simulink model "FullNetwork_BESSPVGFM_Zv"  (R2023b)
settings: Solver=ode15s  StartTime=0.0  StopTime=140  RelTol=1e-3
PreLoadFcn:
  | Ts=50e-6;
model workspace (MAT data in the model file):
  Cf1 = 0.02
  Cf2 = 0.02
  Kffi1 = 0.9
  Kffi2 = 0.9
  Kffi3 = 0.9
  Kffv1 = 1
  Kffv2 = 1
  Kffv3 = 1
  Ki_cc1 = 5.9
  Ki_cc2 = 5.9
  Ki_cc3 = 5.9
  Ki_q1 = 0.0001
  Ki_q2 = 0.0001
  Ki_q3 = 0.0001
  Ki_vc1 = 150
  Ki_vc2 = 150
  Ki_vc3 = 150
  Kp_cc1 = 0.015
  Kp_cc2 = 0.015
  Kp_vc1 = 15
  Kp_vc2 = 15
  Kp_vc3 = 5
  Lf1 = 4.75e-06
  Lf2 = 4.75e-06
  Rf1 = 0.0005
  Rf2 = 0.0005
  Rf3 = 0.0005
  Rv1 = 0.0003
  Rv2 = 0.0003
  Snom1 = 100000000
  Snom2 = 100000000
  Vdc1 = 2000
  Vdc2 = 2000
  Vdc3 = 2000
  Xv1 = 0.0009
  Xv2 = 0.0009
  fnom1 = 50
  fnom2 = 50
  mp1 = 6.25e-08
  mp2 = 6.25e-08
  nq1 = 4.69166666667e-07
  nq2 = 4.69166666667e-07
  tau1 = 0.001
  tau2 = 0.001
  tau3 = 0.001
  vnom1 = 690
  vnom2 = 690
  vnom3 = 690
undefined symbols (not defined in the file or in its folder): Armidale, DiscIntNeverNeededParam, find_system, Gunnedah, Innerell, Ion, Lithium, Morree, Narrabri, Tamworth
libraries: spsThreePhaseBreakerLib x41, simulink_extras x16, spsThreePhaseVIMeasurementLib x14, spsThreePhaseSeriesRLCLoadLib x14, spsabctodq0Lib x12, spsThreePhaseTransformerTwoWindingsLib x11, slpidlib x8, powerlib_extras x8, spsLoadFlowBusLib x8, spsThreePhasePISectionLineLib x8, spsFirstOrderFilterLib x6, simulink x6
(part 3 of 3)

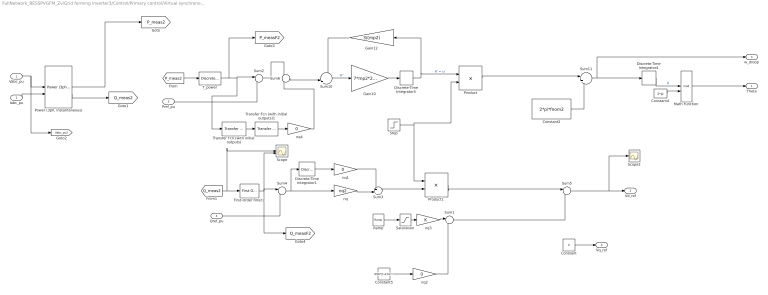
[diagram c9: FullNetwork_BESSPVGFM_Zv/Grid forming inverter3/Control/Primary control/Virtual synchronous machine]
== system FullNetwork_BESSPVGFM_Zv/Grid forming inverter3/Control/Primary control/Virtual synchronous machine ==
  Vabc_pu : Inport
  Iabc_pu : Inport  Port=2
  Pref_pu : Inport  Port=3
  Qref_pu : Inport  Port=4
  Constant : Constant  Value=0
  Constant2 : Constant  Value=2*pi*fnom2
  Constant4 : Constant  Value=2*pi
  Constant5 : Constant  Value=690*(1.414/1.732)
  Discrete-Time Integrator1 : DiscreteIntegrator  gainval=Ki_q  SampleTime=Ts  LimitOutput=on  ICPrevOutput=DiscIntNeverNeededParam  ICPrevScaledInput=DiscIntNeverNeededParam
  Discrete-Time Integrator4 : DiscreteIntegrator  SampleTime=-1  ICPrevOutput=DiscIntNeverNeededParam  ICPrevScaledInput=DiscIntNeverNeededParam
  Discrete-Time Integrator5 : DiscreteIntegrator  SampleTime=-1  ICPrevOutput=DiscIntNeverNeededParam  ICPrevScaledInput=DiscIntNeverNeededParam
  First-Order Filter1 : spsFirstOrderFilterLib/First-Order Filter  FilterType=Lowpass  Tc=tau2  Ts=Ts  Initialize=off  Vac_Init=[0, 0, 60]  Vdc_Init=0  PlotResponse=off  FreqRange="[0,  200,  1]"
  Gain10 : Gain  Gain=7*mp2*2*pi*fnom
  Gain12 : Gain  Gain=3/(mp2)
  Math Function : Math  Operator=mod  SignedPower=on
  "Power (3ph, Instantaneous)" : spsPower3phInstantaneousLib/Power (3ph, Instantaneous)
  Product : Product
  Product1 : Product
  Ramp : simulink/Sources/Ramp  slope=100  start=1  InitialOutput=0
  Saturation : Saturate  UpperLimit=563.5  LowerLimit=0  LinearizeAsGain=off  ZeroCross=off
  Scope : Scope  NumInputPorts=2
  Scope2 : Scope
  Step : Step  Time=0  SampleTime=0
  Sum1 : Sum  Inputs=|++  InputSameDT=on  SaturateOnIntegerOverflow=on
  Sum10 : Sum  Inputs=-|+||
  Sum11 : Sum  Inputs=|++
  Sum2 : Sum  Inputs=|-+  InputSameDT=on  SaturateOnIntegerOverflow=on
  Sum3 : Sum  Inputs=++|  InputSameDT=on  SaturateOnIntegerOverflow=on
  Sum4 : Sum  Inputs=|-+  InputSameDT=on  SaturateOnIntegerOverflow=on
  Sum5 : Sum  Inputs=|++  InputSameDT=on  SaturateOnIntegerOverflow=on
  Sum6 : Sum  Inputs=+-  InputSameDT=on  SaturateOnIntegerOverflow=on
  T_power : powerlib_extras/Discrete  Control Blocks/Discrete 1st-Order Filter  FilterType=Lowpass  Tc=tau2  Ts=Ts  Initialize=on  Vac_Init=[0 0 0]  Vdc_Init=1  PlotResponse=off  param1=[1 500 0.1]
  Transfer Fcn (with initial outputs) : simulink_extras/Additional Linear/Transfer Fcn (with initial outputs)  N=[0.15 1]  D="[0.03  1]"  Y0=0  U0=0
  Transfer Fcn (with initial outputs)1 : simulink_extras/Additional Linear/Transfer Fcn (with initial outputs)  N=[0.2 0 ]  D=[0.2 1]  Y0=0  U0=0
  nq : Gain  Gain=nq2
  nq1 : Gain  Gain=0
  nq2 : Gain  Gain=0
  nq3 : Gain
  nq4 : Gain  Gain=0
  Theta : Outport
  Vd_ref : Outport  Port=2
  Vq_ref : Outport  Port=3
  w_droop : Outport  Port=4
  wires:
  Constant4/1 -> Math Function/2
  Pref_pu/1 -> Sum2/2
  Vabc_pu/1 -> [Vabc_pu2], "Power (3ph, Instantaneous)"/1
  Iabc_pu/1 -> "Power (3ph, Instantaneous)"/2
  "Power (3ph, Instantaneous)"/1 -> [P_meas2]
  "Power (3ph, Instantaneous)"/2 -> [Q_meas2]
  [P_meas2] -> T_power/1
  Math Function/1 -> Theta/1
  Discrete-Time Integrator5/1 -> Product/1, Gain12/1  "θ' = ω"
  Discrete-Time Integrator4/1 -> Math Function/1  "θ"
  Sum10/1 -> Gain10/1  "θ''"
  Gain10/1 -> Discrete-Time Integrator5/1
  Gain12/1 -> Sum10/1
  Sum11/1 -> Discrete-Time Integrator4/1, w_droop/1
  Constant2/1 -> Sum11/2
  nq/1 -> Sum3/2
  Sum4/1 -> nq/1, Discrete-Time Integrator1/1
  First-Order Filter1/1 -> [Q_measF2], Scope/2, Sum4/1
  [Q_meas2] -> Scope/1, First-Order Filter1/1
  Qref_pu/1 -> Sum4/2
  Constant/1 -> Vq_ref/1
  Discrete-Time Integrator1/1 -> nq1/1
  nq1/1 -> Sum3/1
  Sum3/1 -> Product1/2
  Product1/1 -> Sum5/1
  Ramp/1 -> Saturation/1
  Product/1 -> Sum11/1
  Step/1 -> Product/2, Product1/1
  Sum1/1 -> Sum5/2
  Constant5/1 -> nq2/1
  nq2/1 -> Sum1/2
  Saturation/1 -> nq3/1
  nq3/1 -> Sum1/1
  Sum5/1 -> Scope2/1, Vd_ref/1
  Transfer Fcn (with initial outputs)/1 -> Transfer Fcn (with initial outputs)1/1
  Transfer Fcn (with initial outputs)1/1 -> nq4/1
  T_power/1 -> [P_measF2], Transfer Fcn (with initial outputs)/1, Sum2/1
  Sum2/1 -> Sum6/1
  Sum6/1 -> Sum10/2
  nq4/1 -> Sum6/2

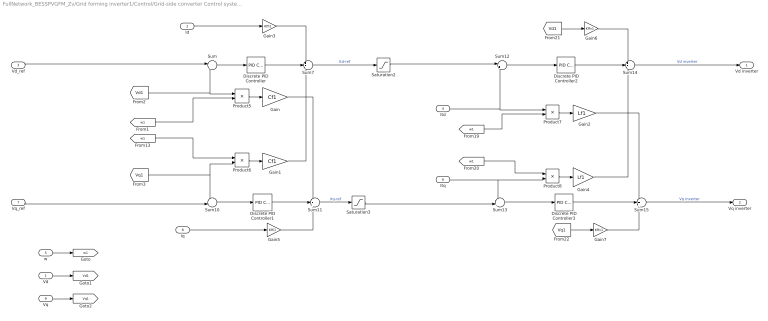
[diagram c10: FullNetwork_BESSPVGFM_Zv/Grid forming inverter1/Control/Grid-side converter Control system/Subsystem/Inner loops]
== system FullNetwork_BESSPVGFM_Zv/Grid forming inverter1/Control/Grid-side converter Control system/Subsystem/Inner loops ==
  Vd : Inport
  Id : Inport  Port=2
  Vd_ref : Inport  Port=3
  Itd : Inport  Port=4
  w : Inport  Port=5
  Itq : Inport  Port=6
  Vq_ref : Inport  Port=7
  Iq : Inport  Port=8
  Vq : Inport  Port=9
  Discrete PID Controller : slpidlib/PID Controller  Controller=PI  Form=Parallel  TimeDomain=Discrete-time  UseExternalTs=off  SampleTime=Ts  IntegratorMethod=Forward Euler  FilterMethod=Forward Euler  ControllerParametersSource=internal  P=Kp_vc1  I=Ki_vc1  UseKiTs=off  D=0  N=100  UseFilter=on  TunerSelectOption=Transfer Function Based (PID Tuner App)  InitialConditionSource=internal  InitialConditionForIntegrator=0  InitialConditionForFilter=0  DifferentiatorICPrevScaledInput=0  ExternalReset=none  TrackingMode=off  Kt=1  LimitOutput=off  SatLimitsSource=internal  UpperSaturationLimit=inf  LowerSaturationLimit=-inf  LinearizeAsGain=off  AntiWindupMode=none  Kb=1  LimitIntegrator=off  UpperIntegratorSaturationLimit=inf  LowerIntegratorSaturationLimit=-inf  POutMin=[]  POutMax=[]  IOutMin=[]  IOutMax=[]  DOutMin=[]  DOutMax=[]  NOutMin=[]  NOutMax=[]  SumOutMin=[]  SumOutMax=[]  SaturationOutMin=[]  SaturationOutMax=[]  PParamMin=[]  PParamMax=[]  IParamMin=[]  IParamMax=[]  DParamMin=[]  DParamMax=[]  NParamMin=[]  NParamMax=[]  KbParamMin=[]  KbParamMax=[]  KtParamMin=[]  KtParamMax=[]  KbOutMin=[]  KbOutMax=[]  KtOutMin=[]  KtOutMax=[]  IntegratorOutMin=[]  IntegratorOutMax=[]  FilterOutMin=[]  FilterOutMax=[]  SumI1OutMin=[]  SumI1OutMax=[]  SumI2OutMin=[]  SumI2OutMax=[]  SumI3OutMin=[]  SumI3OutMax=[]  SumI4OutMin=[]  SumI4OutMax=[]  SumDOutMin=[]  SumDOutMax=[]  DifferentiatorOutMin=[]  DifferentiatorOutMax=[]  FilterDiffOutCoefMin=[]  FilterDiffOutCoefMax=[]  ReciprocalOutMin=[]  ReciprocalOutMax=[]  SumDenOutMin=[]  SumDenOutMax=[]  SumNumOutMin=[]  SumNumOutMax=[]  DivideOutMin=[]  DivideOutMax=[]  UdiffTsProdOutMin=[]  UdiffTsProdOutMax=[]  NTsProdOutMin=[]  NTsProdOutMax=[]  UintegralTsProdOutMin=[]  UintegralTsProdOutMax=[]  UngainTsProdOutMin=[]  UngainTsProdOutMax=[]  ClampingZeroOutDataTypeStr=Inherit: Inherit via back propagation  ClampingZeroOutMin=[]  ClampingZeroOutMax=[]  FilterDenConstantOutDataTypeStr=Inherit: Inherit via back propagation  FilterDenConstantOutMin=[]  FilterDenConstantOutMax=[]  PCopyOutDataTypeStr=Inherit: Inherit via back propagation  PCopyOutMin=[]  PCopyOutMax=[]  NCopyOutDataTypeStr=Inherit: Inherit via back propagation  NCopyOutMin=[]  NCopyOutMax=[]  IntegratorContinuousStateAttributes=''  IntegratorStateMustResolveToSignalObject=off  IntegratorRTWStateStorageClass=Auto  FilterContinuousStateAttributes=''  FilterStateMustResolveToSignalObject=off  FilterRTWStateStorageClass=Auto  ParallelPVariant=InternalParameters  IdealPVariant=Disabled  IVariant=InternalParameters  DVariant=Disabled  IntegratorVariant=Discrete  SatVariant=Disabled  AWVariant=Passthrough  PCopyVariant=Disabled  TRVariant=Disabled  FdbkBlocksVariant=Forward  IdealPFdbkVariant=Disabled  SatFdbkVariant=Disabled  DerivativeFilterVariant=Disabled  NVariant=Disabled  NCopyVariant=Disabled_SignalSpec  FilterICVariant=Disabled  IntegratorICVariant=InternalICs  ExternalResetVariant=Disabled  TRSumVariant=Passthrough  SumFdbkVariant=Disabled  SumVariant=Sum_PI  TsampFilterVariant=InternalTs  TsampNgainVariant=Passthrough  TsampIntegralVariant=Disabled_SignalSpec  ExternalSaturationOutDataTypeStr=Inherit: Same as second input
  Discrete PID Controller1 : slpidlib/PID Controller  Controller=PI  Form=Parallel  TimeDomain=Discrete-time  UseExternalTs=off  SampleTime=Ts  IntegratorMethod=Forward Euler  FilterMethod=Forward Euler  ControllerParametersSource=internal  P=Kp_vc1  I=Ki_vc1  UseKiTs=off  D=0  N=100  UseFilter=on  TunerSelectOption=Transfer Function Based (PID Tuner App)  InitialConditionSource=internal  InitialConditionForIntegrator=0  InitialConditionForFilter=0  DifferentiatorICPrevScaledInput=0  ExternalReset=none  TrackingMode=off  Kt=1  LimitOutput=off  SatLimitsSource=internal  UpperSaturationLimit=inf  LowerSaturationLimit=-inf  LinearizeAsGain=off  AntiWindupMode=none  Kb=1  LimitIntegrator=off  UpperIntegratorSaturationLimit=inf  LowerIntegratorSaturationLimit=-inf  POutMin=[]  POutMax=[]  IOutMin=[]  IOutMax=[]  DOutMin=[]  DOutMax=[]  NOutMin=[]  NOutMax=[]  SumOutMin=[]  SumOutMax=[]  SaturationOutMin=[]  SaturationOutMax=[]  PParamMin=[]  PParamMax=[]  IParamMin=[]  IParamMax=[]  DParamMin=[]  DParamMax=[]  NParamMin=[]  NParamMax=[]  KbParamMin=[]  KbParamMax=[]  KtParamMin=[]  KtParamMax=[]  KbOutMin=[]  KbOutMax=[]  KtOutMin=[]  KtOutMax=[]  IntegratorOutMin=[]  IntegratorOutMax=[]  FilterOutMin=[]  FilterOutMax=[]  SumI1OutMin=[]  SumI1OutMax=[]  SumI2OutMin=[]  SumI2OutMax=[]  SumI3OutMin=[]  SumI3OutMax=[]  SumI4OutMin=[]  SumI4OutMax=[]  SumDOutMin=[]  SumDOutMax=[]  DifferentiatorOutMin=[]  DifferentiatorOutMax=[]  FilterDiffOutCoefMin=[]  FilterDiffOutCoefMax=[]  ReciprocalOutMin=[]  ReciprocalOutMax=[]  SumDenOutMin=[]  SumDenOutMax=[]  SumNumOutMin=[]  SumNumOutMax=[]  DivideOutMin=[]  DivideOutMax=[]  UdiffTsProdOutMin=[]  UdiffTsProdOutMax=[]  NTsProdOutMin=[]  NTsProdOutMax=[]  UintegralTsProdOutMin=[]  UintegralTsProdOutMax=[]  UngainTsProdOutMin=[]  UngainTsProdOutMax=[]  ClampingZeroOutDataTypeStr=Inherit: Inherit via back propagation  ClampingZeroOutMin=[]  ClampingZeroOutMax=[]  FilterDenConstantOutDataTypeStr=Inherit: Inherit via back propagation  FilterDenConstantOutMin=[]  FilterDenConstantOutMax=[]  PCopyOutDataTypeStr=Inherit: Inherit via back propagation  PCopyOutMin=[]  PCopyOutMax=[]  NCopyOutDataTypeStr=Inherit: Inherit via back propagation  NCopyOutMin=[]  NCopyOutMax=[]  IntegratorContinuousStateAttributes=''  IntegratorStateMustResolveToSignalObject=off  IntegratorRTWStateStorageClass=Auto  FilterContinuousStateAttributes=''  FilterStateMustResolveToSignalObject=off  FilterRTWStateStorageClass=Auto  ParallelPVariant=InternalParameters  IdealPVariant=Disabled  IVariant=InternalParameters  DVariant=Disabled  IntegratorVariant=Discrete  SatVariant=Disabled  AWVariant=Passthrough  PCopyVariant=Disabled  TRVariant=Disabled  FdbkBlocksVariant=Forward  IdealPFdbkVariant=Disabled  SatFdbkVariant=Disabled  DerivativeFilterVariant=Disabled  NVariant=Disabled  NCopyVariant=Disabled_SignalSpec  FilterICVariant=Disabled  IntegratorICVariant=InternalICs  ExternalResetVariant=Disabled  TRSumVariant=Passthrough  SumFdbkVariant=Disabled  SumVariant=Sum_PI  TsampFilterVariant=InternalTs  TsampNgainVariant=Passthrough  TsampIntegralVariant=Disabled_SignalSpec  ExternalSaturationOutDataTypeStr=Inherit: Same as second input
  Discrete PID Controller2 : slpidlib/PID Controller  Controller=PI  Form=Parallel  TimeDomain=Discrete-time  UseExternalTs=off  SampleTime=Ts  IntegratorMethod=Forward Euler  FilterMethod=Forward Euler  ControllerParametersSource=internal  P=Kp_cc1  I=Ki_cc1  UseKiTs=off  D=0  N=100  UseFilter=on  TunerSelectOption=Transfer Function Based (PID Tuner App)  InitialConditionSource=internal  InitialConditionForIntegrator=0  InitialConditionForFilter=0  DifferentiatorICPrevScaledInput=0  ExternalReset=none  TrackingMode=off  Kt=1  LimitOutput=off  SatLimitsSource=internal  UpperSaturationLimit=inf  LowerSaturationLimit=-inf  LinearizeAsGain=off  AntiWindupMode=none  Kb=1  LimitIntegrator=off  UpperIntegratorSaturationLimit=inf  LowerIntegratorSaturationLimit=-inf  POutMin=[]  POutMax=[]  IOutMin=[]  IOutMax=[]  DOutMin=[]  DOutMax=[]  NOutMin=[]  NOutMax=[]  SumOutMin=[]  SumOutMax=[]  SaturationOutMin=[]  SaturationOutMax=[]  PParamMin=[]  PParamMax=[]  IParamMin=[]  IParamMax=[]  DParamMin=[]  DParamMax=[]  NParamMin=[]  NParamMax=[]  KbParamMin=[]  KbParamMax=[]  KtParamMin=[]  KtParamMax=[]  KbOutMin=[]  KbOutMax=[]  KtOutMin=[]  KtOutMax=[]  IntegratorOutMin=[]  IntegratorOutMax=[]  FilterOutMin=[]  FilterOutMax=[]  SumI1OutMin=[]  SumI1OutMax=[]  SumI2OutMin=[]  SumI2OutMax=[]  SumI3OutMin=[]  SumI3OutMax=[]  SumI4OutMin=[]  SumI4OutMax=[]  SumDOutMin=[]  SumDOutMax=[]  DifferentiatorOutMin=[]  DifferentiatorOutMax=[]  FilterDiffOutCoefMin=[]  FilterDiffOutCoefMax=[]  ReciprocalOutMin=[]  ReciprocalOutMax=[]  SumDenOutMin=[]  SumDenOutMax=[]  SumNumOutMin=[]  SumNumOutMax=[]  DivideOutMin=[]  DivideOutMax=[]  UdiffTsProdOutMin=[]  UdiffTsProdOutMax=[]  NTsProdOutMin=[]  NTsProdOutMax=[]  UintegralTsProdOutMin=[]  UintegralTsProdOutMax=[]  UngainTsProdOutMin=[]  UngainTsProdOutMax=[]  ClampingZeroOutDataTypeStr=Inherit: Inherit via back propagation  ClampingZeroOutMin=[]  ClampingZeroOutMax=[]  FilterDenConstantOutDataTypeStr=Inherit: Inherit via back propagation  FilterDenConstantOutMin=[]  FilterDenConstantOutMax=[]  PCopyOutDataTypeStr=Inherit: Inherit via back propagation  PCopyOutMin=[]  PCopyOutMax=[]  NCopyOutDataTypeStr=Inherit: Inherit via back propagation  NCopyOutMin=[]  NCopyOutMax=[]  IntegratorContinuousStateAttributes=''  IntegratorStateMustResolveToSignalObject=off  IntegratorRTWStateStorageClass=Auto  FilterContinuousStateAttributes=''  FilterStateMustResolveToSignalObject=off  FilterRTWStateStorageClass=Auto  ParallelPVariant=InternalParameters  IdealPVariant=Disabled  IVariant=InternalParameters  DVariant=Disabled  IntegratorVariant=Discrete  SatVariant=Disabled  AWVariant=Passthrough  PCopyVariant=Disabled  TRVariant=Disabled  FdbkBlocksVariant=Forward  IdealPFdbkVariant=Disabled  SatFdbkVariant=Disabled  DerivativeFilterVariant=Disabled  NVariant=Disabled  NCopyVariant=Disabled_SignalSpec  FilterICVariant=Disabled  IntegratorICVariant=InternalICs  ExternalResetVariant=Disabled  TRSumVariant=Passthrough  SumFdbkVariant=Disabled  SumVariant=Sum_PI  TsampFilterVariant=InternalTs  TsampNgainVariant=Passthrough  TsampIntegralVariant=Disabled_SignalSpec  ExternalSaturationOutDataTypeStr=Inherit: Same as second input
  Discrete PID Controller3 : slpidlib/PID Controller  Controller=PI  Form=Parallel  TimeDomain=Discrete-time  UseExternalTs=off  SampleTime=Ts  IntegratorMethod=Forward Euler  FilterMethod=Forward Euler  ControllerParametersSource=internal  P=Kp_cc1  I=Ki_cc1  UseKiTs=off  D=0  N=100  UseFilter=on  TunerSelectOption=Transfer Function Based (PID Tuner App)  InitialConditionSource=internal  InitialConditionForIntegrator=0  InitialConditionForFilter=0  DifferentiatorICPrevScaledInput=0  ExternalReset=none  TrackingMode=off  Kt=1  LimitOutput=off  SatLimitsSource=internal  UpperSaturationLimit=inf  LowerSaturationLimit=-inf  LinearizeAsGain=off  AntiWindupMode=none  Kb=1  LimitIntegrator=off  UpperIntegratorSaturationLimit=inf  LowerIntegratorSaturationLimit=-inf  POutMin=[]  POutMax=[]  IOutMin=[]  IOutMax=[]  DOutMin=[]  DOutMax=[]  NOutMin=[]  NOutMax=[]  SumOutMin=[]  SumOutMax=[]  SaturationOutMin=[]  SaturationOutMax=[]  PParamMin=[]  PParamMax=[]  IParamMin=[]  IParamMax=[]  DParamMin=[]  DParamMax=[]  NParamMin=[]  NParamMax=[]  KbParamMin=[]  KbParamMax=[]  KtParamMin=[]  KtParamMax=[]  KbOutMin=[]  KbOutMax=[]  KtOutMin=[]  KtOutMax=[]  IntegratorOutMin=[]  IntegratorOutMax=[]  FilterOutMin=[]  FilterOutMax=[]  SumI1OutMin=[]  SumI1OutMax=[]  SumI2OutMin=[]  SumI2OutMax=[]  SumI3OutMin=[]  SumI3OutMax=[]  SumI4OutMin=[]  SumI4OutMax=[]  SumDOutMin=[]  SumDOutMax=[]  DifferentiatorOutMin=[]  DifferentiatorOutMax=[]  FilterDiffOutCoefMin=[]  FilterDiffOutCoefMax=[]  ReciprocalOutMin=[]  ReciprocalOutMax=[]  SumDenOutMin=[]  SumDenOutMax=[]  SumNumOutMin=[]  SumNumOutMax=[]  DivideOutMin=[]  DivideOutMax=[]  UdiffTsProdOutMin=[]  UdiffTsProdOutMax=[]  NTsProdOutMin=[]  NTsProdOutMax=[]  UintegralTsProdOutMin=[]  UintegralTsProdOutMax=[]  UngainTsProdOutMin=[]  UngainTsProdOutMax=[]  ClampingZeroOutDataTypeStr=Inherit: Inherit via back propagation  ClampingZeroOutMin=[]  ClampingZeroOutMax=[]  FilterDenConstantOutDataTypeStr=Inherit: Inherit via back propagation  FilterDenConstantOutMin=[]  FilterDenConstantOutMax=[]  PCopyOutDataTypeStr=Inherit: Inherit via back propagation  PCopyOutMin=[]  PCopyOutMax=[]  NCopyOutDataTypeStr=Inherit: Inherit via back propagation  NCopyOutMin=[]  NCopyOutMax=[]  IntegratorContinuousStateAttributes=''  IntegratorStateMustResolveToSignalObject=off  IntegratorRTWStateStorageClass=Auto  FilterContinuousStateAttributes=''  FilterStateMustResolveToSignalObject=off  FilterRTWStateStorageClass=Auto  ParallelPVariant=InternalParameters  IdealPVariant=Disabled  IVariant=InternalParameters  DVariant=Disabled  IntegratorVariant=Discrete  SatVariant=Disabled  AWVariant=Passthrough  PCopyVariant=Disabled  TRVariant=Disabled  FdbkBlocksVariant=Forward  IdealPFdbkVariant=Disabled  SatFdbkVariant=Disabled  DerivativeFilterVariant=Disabled  NVariant=Disabled  NCopyVariant=Disabled_SignalSpec  FilterICVariant=Disabled  IntegratorICVariant=InternalICs  ExternalResetVariant=Disabled  TRSumVariant=Passthrough  SumFdbkVariant=Disabled  SumVariant=Sum_PI  TsampFilterVariant=InternalTs  TsampNgainVariant=Passthrough  TsampIntegralVariant=Disabled_SignalSpec  ExternalSaturationOutDataTypeStr=Inherit: Same as second input
  Gain : Gain  Gain=Cf1
  Gain1 : Gain  Gain=Cf1
  Gain2 : Gain  Gain=Lf1
  Gain3 : Gain  Gain=Kffi1
  Gain4 : Gain  Gain=Lf1
  Gain5 : Gain  Gain=Kffi1
  Gain6 : Gain  Gain=Kffv1
  Gain7 : Gain  Gain=Kffv1
  Product{5..8} (4 alike) : Product
  Saturation2 : Saturate  UpperLimit=1.1*0.142*10e6  LowerLimit=-1.2*0.142*10e6  LinearizeAsGain=off  ZeroCross=off
  Saturation3 : Saturate  UpperLimit=1.1*0.106*10e6  LowerLimit=-1.2*0.106*10e6  LinearizeAsGain=off  ZeroCross=off
  Sum : Sum  Inputs=|+-
  Sum10 : Sum  Inputs=-+|
  Sum11 : Sum  Inputs=+++
  Sum12 : Sum  Inputs=|+-
  Sum13 : Sum  Inputs=-+|
  Sum14 : Sum  Inputs=++-
  Sum15 : Sum  Inputs=+++
  Sum7 : Sum  Inputs=++-
  Vd inverter : Outport
  Vq inverter : Outport  Port=2
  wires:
  [Vq1] -> Sum10/1, Product6/2
  Itd/1 -> Sum12/2, Product7/1
  Sum/1 -> Discrete PID Controller/1
  [w1] -> Product8/1
  Iq/1 -> Gain5/1
  Vd_ref/1 -> Sum/1
  [Vq1] -> Gain7/1
  Gain2/1 -> Sum15/1
  [Vd1] -> Gain6/1
  [Vd1] -> Sum/2, Product5/1
  Product5/1 -> Gain/1
  [w1] -> Product5/2
  Sum10/1 -> Discrete PID Controller1/1
  Gain3/1 -> Sum7/1
  Itq/1 -> Sum13/1, Product8/2
  Sum15/1 -> Vq inverter/1  "Vq inverter"
  [w1] -> Product6/1
  Product6/1 -> Gain1/1
  Gain/1 -> Sum11/1
  [w1] -> Product7/2
  Sum12/1 -> Discrete PID Controller2/1
  Vq_ref/1 -> Sum10/2
  Discrete PID Controller/1 -> Sum7/2
  Gain5/1 -> Sum11/3
  Gain4/1 -> Sum14/3
  Sum13/1 -> Discrete PID Controller3/1
  Gain1/1 -> Sum7/3
  Sum14/1 -> Vd inverter/1  "Vd inverter"
  Id/1 -> Gain3/1
  Product7/1 -> Gain2/1
  Product8/1 -> Gain4/1
  Discrete PID Controller2/1 -> Sum14/2
  Discrete PID Controller1/1 -> Sum11/2
  Gain6/1 -> Sum14/1
  Discrete PID Controller3/1 -> Sum15/2
  Gain7/1 -> Sum15/3
  w/1 -> [w1]
  Vd/1 -> [Vd1]
  Vq/1 -> [Vq1]
  Sum7/1 -> Saturation2/1  "Itd-ref"
  Saturation2/1 -> Sum12/1
  Sum11/1 -> Saturation3/1  "itq-ref"
  Saturation3/1 -> Sum13/2

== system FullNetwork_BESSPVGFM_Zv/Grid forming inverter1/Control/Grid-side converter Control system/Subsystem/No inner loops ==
  Vd_ref : Inport
  Vq_ref : Inport  Port=2
  Vd inverter : Outport
  Vq inverter : Outport  Port=2
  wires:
  Vd_ref/1 -> Vd inverter/1
  Vq_ref/1 -> Vq inverter/1

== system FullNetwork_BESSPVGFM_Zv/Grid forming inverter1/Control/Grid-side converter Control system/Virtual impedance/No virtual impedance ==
  Vd_ref : Inport
  Vq_ref : Inport  Port=2
  Vd_ref* : Outport
  Vq_ref* : Outport  Port=2
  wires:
  Vd_ref/1 -> Vd_ref*/1
  Vq_ref/1 -> Vq_ref*/1

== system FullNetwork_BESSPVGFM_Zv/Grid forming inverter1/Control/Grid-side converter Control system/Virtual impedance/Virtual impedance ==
  Vd_ref : Inport
  Id : Inport  Port=2
  Iq : Inport  Port=3
  Vq_ref : Inport  Port=4
  Gain : Gain
  Gain1 : Gain
  Rvir1 : Gain  Gain=Xv1
  Rvir3 : Gain  Gain=Xv1
  Sum1 : Sum  Inputs=-+
  Sum11 : Sum  Inputs=|+-
  Sum12 : Sum  Inputs=-+
  Sum2 : Sum  Inputs=--
  Sum3 : Sum  Inputs=|++++
  Sum4 : Sum  Inputs=++++|
  T_power10 : powerlib_extras/Discrete  Control Blocks/Discrete 1st-Order Filter  FilterType=Lowpass  Tc=0.05  Ts=Ts  Initialize=on  Vac_Init=[0 0 0]  Vdc_Init=1  PlotResponse=off  param1=[1 200 0.1 ]
  T_power11 : powerlib_extras/Discrete  Control Blocks/Discrete 1st-Order Filter  FilterType=Lowpass  Tc=0.05  Ts=Ts  Initialize=on  Vac_Init=[0 0 0]  Vdc_Init=1  PlotResponse=off  param1=[1 200 0.1 ]
  T_power3 : powerlib_extras/Discrete  Control Blocks/Discrete 1st-Order Filter  FilterType=Lowpass  Tc=tau  Ts=Ts  Initialize=on  Vac_Init=[0 0 0]  Vdc_Init=1  PlotResponse=off  param1=[1 200 0.1]
  Transfer Fcn (with initial outputs){1..4} (4 alike) : simulink_extras/Additional Linear/Transfer Fcn (with initial outputs)  N=[0.2 0 ]  D=[0.2 1]  Y0=0  U0=0
  Xvir1 : Gain  Gain=Rv1
  Xvir2 : Gain  Gain=-10*Rv1
  Xvir3 : Gain  Gain=Rv1
  Xvir4 : Gain  Gain=-10*Rv1
  Xvir5 : Gain  Gain=10*Xv1
  Xvir6 : Gain  Gain=-10*Xv1
  Vd_ref* : Outport
  Vq_ref* : Outport  Port=2
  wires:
  Sum2/1 -> T_power11/1, Sum4/1
  Sum1/1 -> T_power10/1, Sum3/3
  Vq_ref/1 -> Sum4/2
  Vd_ref/1 -> Sum3/2
  Id/1 -> [Id1]
  Iq/1 -> [Iq1]
  [Id1] -> Xvir1/1
  Xvir1/1 -> Sum1/1
  [Iq1] -> Rvir3/1
  Rvir3/1 -> Sum1/2
  Rvir1/1 -> Sum2/1
  [Id1] -> Rvir1/1
  [Iq1] -> Xvir3/1
  Xvir3/1 -> Sum2/2
  Sum11/1 -> Vd_ref*/1
  Sum3/1 -> Sum11/1
  Sum12/1 -> Vq_ref*/1
  Sum4/1 -> Sum12/2
  T_power10/1 -> Gain/1
  Gain/1 -> Sum11/2
  T_power11/1 -> Gain1/1
  Gain1/1 -> Sum12/1
  Xvir2/1 -> Sum3/1
  Transfer Fcn (with initial outputs)1/1 -> Xvir2/1
  [Id1] -> Transfer Fcn (with initial outputs)1/1
  Xvir4/1 -> Sum4/3
  Transfer Fcn (with initial outputs)2/1 -> Xvir4/1
  [Iq1] -> Transfer Fcn (with initial outputs)2/1
  Transfer Fcn (with initial outputs)3/1 -> Xvir5/1
  [Iq1] -> Transfer Fcn (with initial outputs)3/1
  Xvir5/1 -> Sum3/4
  Transfer Fcn (with initial outputs)4/1 -> Xvir6/1
  [Id1] -> Transfer Fcn (with initial outputs)4/1
  Xvir6/1 -> Sum4/4

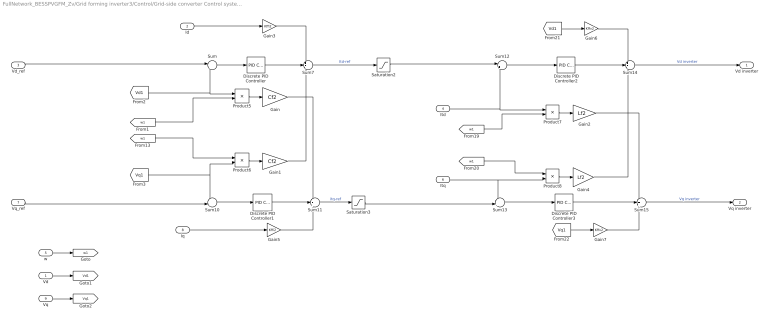
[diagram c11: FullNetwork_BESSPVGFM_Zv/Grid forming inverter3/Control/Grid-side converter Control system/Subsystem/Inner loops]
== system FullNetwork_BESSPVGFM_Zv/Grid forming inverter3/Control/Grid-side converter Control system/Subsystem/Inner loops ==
  Vd : Inport
  Id : Inport  Port=2
  Vd_ref : Inport  Port=3
  Itd : Inport  Port=4
  w : Inport  Port=5
  Itq : Inport  Port=6
  Vq_ref : Inport  Port=7
  Iq : Inport  Port=8
  Vq : Inport  Port=9
  Discrete PID Controller : slpidlib/PID Controller  Controller=PI  Form=Parallel  TimeDomain=Discrete-time  UseExternalTs=off  SampleTime=Ts  IntegratorMethod=Forward Euler  FilterMethod=Forward Euler  ControllerParametersSource=internal  P=Kp_vc2  I=Ki_vc2  UseKiTs=off  D=0  N=100  UseFilter=on  TunerSelectOption=Transfer Function Based (PID Tuner App)  InitialConditionSource=internal  InitialConditionForIntegrator=0  InitialConditionForFilter=0  DifferentiatorICPrevScaledInput=0  ExternalReset=none  TrackingMode=off  Kt=1  LimitOutput=off  SatLimitsSource=internal  UpperSaturationLimit=inf  LowerSaturationLimit=-inf  LinearizeAsGain=off  AntiWindupMode=none  Kb=1  LimitIntegrator=off  UpperIntegratorSaturationLimit=inf  LowerIntegratorSaturationLimit=-inf  POutMin=[]  POutMax=[]  IOutMin=[]  IOutMax=[]  DOutMin=[]  DOutMax=[]  NOutMin=[]  NOutMax=[]  SumOutMin=[]  SumOutMax=[]  SaturationOutMin=[]  SaturationOutMax=[]  PParamMin=[]  PParamMax=[]  IParamMin=[]  IParamMax=[]  DParamMin=[]  DParamMax=[]  NParamMin=[]  NParamMax=[]  KbParamMin=[]  KbParamMax=[]  KtParamMin=[]  KtParamMax=[]  KbOutMin=[]  KbOutMax=[]  KtOutMin=[]  KtOutMax=[]  IntegratorOutMin=[]  IntegratorOutMax=[]  FilterOutMin=[]  FilterOutMax=[]  SumI1OutMin=[]  SumI1OutMax=[]  SumI2OutMin=[]  SumI2OutMax=[]  SumI3OutMin=[]  SumI3OutMax=[]  SumI4OutMin=[]  SumI4OutMax=[]  SumDOutMin=[]  SumDOutMax=[]  DifferentiatorOutMin=[]  DifferentiatorOutMax=[]  FilterDiffOutCoefMin=[]  FilterDiffOutCoefMax=[]  ReciprocalOutMin=[]  ReciprocalOutMax=[]  SumDenOutMin=[]  SumDenOutMax=[]  SumNumOutMin=[]  SumNumOutMax=[]  DivideOutMin=[]  DivideOutMax=[]  UdiffTsProdOutMin=[]  UdiffTsProdOutMax=[]  NTsProdOutMin=[]  NTsProdOutMax=[]  UintegralTsProdOutMin=[]  UintegralTsProdOutMax=[]  UngainTsProdOutMin=[]  UngainTsProdOutMax=[]  ClampingZeroOutDataTypeStr=Inherit: Inherit via back propagation  ClampingZeroOutMin=[]  ClampingZeroOutMax=[]  FilterDenConstantOutDataTypeStr=Inherit: Inherit via back propagation  FilterDenConstantOutMin=[]  FilterDenConstantOutMax=[]  PCopyOutDataTypeStr=Inherit: Inherit via back propagation  PCopyOutMin=[]  PCopyOutMax=[]  NCopyOutDataTypeStr=Inherit: Inherit via back propagation  NCopyOutMin=[]  NCopyOutMax=[]  IntegratorContinuousStateAttributes=''  IntegratorStateMustResolveToSignalObject=off  IntegratorRTWStateStorageClass=Auto  FilterContinuousStateAttributes=''  FilterStateMustResolveToSignalObject=off  FilterRTWStateStorageClass=Auto  ParallelPVariant=InternalParameters  IdealPVariant=Disabled  IVariant=InternalParameters  DVariant=Disabled  IntegratorVariant=Discrete  SatVariant=Disabled  AWVariant=Passthrough  PCopyVariant=Disabled  TRVariant=Disabled  FdbkBlocksVariant=Forward  IdealPFdbkVariant=Disabled  SatFdbkVariant=Disabled  DerivativeFilterVariant=Disabled  NVariant=Disabled  NCopyVariant=Disabled_SignalSpec  FilterICVariant=Disabled  IntegratorICVariant=InternalICs  ExternalResetVariant=Disabled  TRSumVariant=Passthrough  SumFdbkVariant=Disabled  SumVariant=Sum_PI  TsampFilterVariant=InternalTs  TsampNgainVariant=Passthrough  TsampIntegralVariant=Disabled_SignalSpec  ExternalSaturationOutDataTypeStr=Inherit: Same as second input
  Discrete PID Controller1 : slpidlib/PID Controller  Controller=PI  Form=Parallel  TimeDomain=Discrete-time  UseExternalTs=off  SampleTime=Ts  IntegratorMethod=Forward Euler  FilterMethod=Forward Euler  ControllerParametersSource=internal  P=Kp_vc2  I=Ki_vc2  UseKiTs=off  D=0  N=100  UseFilter=on  TunerSelectOption=Transfer Function Based (PID Tuner App)  InitialConditionSource=internal  InitialConditionForIntegrator=0  InitialConditionForFilter=0  DifferentiatorICPrevScaledInput=0  ExternalReset=none  TrackingMode=off  Kt=1  LimitOutput=off  SatLimitsSource=internal  UpperSaturationLimit=inf  LowerSaturationLimit=-inf  LinearizeAsGain=off  AntiWindupMode=none  Kb=1  LimitIntegrator=off  UpperIntegratorSaturationLimit=inf  LowerIntegratorSaturationLimit=-inf  POutMin=[]  POutMax=[]  IOutMin=[]  IOutMax=[]  DOutMin=[]  DOutMax=[]  NOutMin=[]  NOutMax=[]  SumOutMin=[]  SumOutMax=[]  SaturationOutMin=[]  SaturationOutMax=[]  PParamMin=[]  PParamMax=[]  IParamMin=[]  IParamMax=[]  DParamMin=[]  DParamMax=[]  NParamMin=[]  NParamMax=[]  KbParamMin=[]  KbParamMax=[]  KtParamMin=[]  KtParamMax=[]  KbOutMin=[]  KbOutMax=[]  KtOutMin=[]  KtOutMax=[]  IntegratorOutMin=[]  IntegratorOutMax=[]  FilterOutMin=[]  FilterOutMax=[]  SumI1OutMin=[]  SumI1OutMax=[]  SumI2OutMin=[]  SumI2OutMax=[]  SumI3OutMin=[]  SumI3OutMax=[]  SumI4OutMin=[]  SumI4OutMax=[]  SumDOutMin=[]  SumDOutMax=[]  DifferentiatorOutMin=[]  DifferentiatorOutMax=[]  FilterDiffOutCoefMin=[]  FilterDiffOutCoefMax=[]  ReciprocalOutMin=[]  ReciprocalOutMax=[]  SumDenOutMin=[]  SumDenOutMax=[]  SumNumOutMin=[]  SumNumOutMax=[]  DivideOutMin=[]  DivideOutMax=[]  UdiffTsProdOutMin=[]  UdiffTsProdOutMax=[]  NTsProdOutMin=[]  NTsProdOutMax=[]  UintegralTsProdOutMin=[]  UintegralTsProdOutMax=[]  UngainTsProdOutMin=[]  UngainTsProdOutMax=[]  ClampingZeroOutDataTypeStr=Inherit: Inherit via back propagation  ClampingZeroOutMin=[]  ClampingZeroOutMax=[]  FilterDenConstantOutDataTypeStr=Inherit: Inherit via back propagation  FilterDenConstantOutMin=[]  FilterDenConstantOutMax=[]  PCopyOutDataTypeStr=Inherit: Inherit via back propagation  PCopyOutMin=[]  PCopyOutMax=[]  NCopyOutDataTypeStr=Inherit: Inherit via back propagation  NCopyOutMin=[]  NCopyOutMax=[]  IntegratorContinuousStateAttributes=''  IntegratorStateMustResolveToSignalObject=off  IntegratorRTWStateStorageClass=Auto  FilterContinuousStateAttributes=''  FilterStateMustResolveToSignalObject=off  FilterRTWStateStorageClass=Auto  ParallelPVariant=InternalParameters  IdealPVariant=Disabled  IVariant=InternalParameters  DVariant=Disabled  IntegratorVariant=Discrete  SatVariant=Disabled  AWVariant=Passthrough  PCopyVariant=Disabled  TRVariant=Disabled  FdbkBlocksVariant=Forward  IdealPFdbkVariant=Disabled  SatFdbkVariant=Disabled  DerivativeFilterVariant=Disabled  NVariant=Disabled  NCopyVariant=Disabled_SignalSpec  FilterICVariant=Disabled  IntegratorICVariant=InternalICs  ExternalResetVariant=Disabled  TRSumVariant=Passthrough  SumFdbkVariant=Disabled  SumVariant=Sum_PI  TsampFilterVariant=InternalTs  TsampNgainVariant=Passthrough  TsampIntegralVariant=Disabled_SignalSpec  ExternalSaturationOutDataTypeStr=Inherit: Same as second input
  Discrete PID Controller2 : slpidlib/PID Controller  Controller=PI  Form=Parallel  TimeDomain=Discrete-time  UseExternalTs=off  SampleTime=Ts  IntegratorMethod=Forward Euler  FilterMethod=Forward Euler  ControllerParametersSource=internal  P=Kp_cc2  I=Ki_cc2  UseKiTs=off  D=0  N=100  UseFilter=on  TunerSelectOption=Transfer Function Based (PID Tuner App)  InitialConditionSource=internal  InitialConditionForIntegrator=0  InitialConditionForFilter=0  DifferentiatorICPrevScaledInput=0  ExternalReset=none  TrackingMode=off  Kt=1  LimitOutput=off  SatLimitsSource=internal  UpperSaturationLimit=inf  LowerSaturationLimit=-inf  LinearizeAsGain=off  AntiWindupMode=none  Kb=1  LimitIntegrator=off  UpperIntegratorSaturationLimit=inf  LowerIntegratorSaturationLimit=-inf  POutMin=[]  POutMax=[]  IOutMin=[]  IOutMax=[]  DOutMin=[]  DOutMax=[]  NOutMin=[]  NOutMax=[]  SumOutMin=[]  SumOutMax=[]  SaturationOutMin=[]  SaturationOutMax=[]  PParamMin=[]  PParamMax=[]  IParamMin=[]  IParamMax=[]  DParamMin=[]  DParamMax=[]  NParamMin=[]  NParamMax=[]  KbParamMin=[]  KbParamMax=[]  KtParamMin=[]  KtParamMax=[]  KbOutMin=[]  KbOutMax=[]  KtOutMin=[]  KtOutMax=[]  IntegratorOutMin=[]  IntegratorOutMax=[]  FilterOutMin=[]  FilterOutMax=[]  SumI1OutMin=[]  SumI1OutMax=[]  SumI2OutMin=[]  SumI2OutMax=[]  SumI3OutMin=[]  SumI3OutMax=[]  SumI4OutMin=[]  SumI4OutMax=[]  SumDOutMin=[]  SumDOutMax=[]  DifferentiatorOutMin=[]  DifferentiatorOutMax=[]  FilterDiffOutCoefMin=[]  FilterDiffOutCoefMax=[]  ReciprocalOutMin=[]  ReciprocalOutMax=[]  SumDenOutMin=[]  SumDenOutMax=[]  SumNumOutMin=[]  SumNumOutMax=[]  DivideOutMin=[]  DivideOutMax=[]  UdiffTsProdOutMin=[]  UdiffTsProdOutMax=[]  NTsProdOutMin=[]  NTsProdOutMax=[]  UintegralTsProdOutMin=[]  UintegralTsProdOutMax=[]  UngainTsProdOutMin=[]  UngainTsProdOutMax=[]  ClampingZeroOutDataTypeStr=Inherit: Inherit via back propagation  ClampingZeroOutMin=[]  ClampingZeroOutMax=[]  FilterDenConstantOutDataTypeStr=Inherit: Inherit via back propagation  FilterDenConstantOutMin=[]  FilterDenConstantOutMax=[]  PCopyOutDataTypeStr=Inherit: Inherit via back propagation  PCopyOutMin=[]  PCopyOutMax=[]  NCopyOutDataTypeStr=Inherit: Inherit via back propagation  NCopyOutMin=[]  NCopyOutMax=[]  IntegratorContinuousStateAttributes=''  IntegratorStateMustResolveToSignalObject=off  IntegratorRTWStateStorageClass=Auto  FilterContinuousStateAttributes=''  FilterStateMustResolveToSignalObject=off  FilterRTWStateStorageClass=Auto  ParallelPVariant=InternalParameters  IdealPVariant=Disabled  IVariant=InternalParameters  DVariant=Disabled  IntegratorVariant=Discrete  SatVariant=Disabled  AWVariant=Passthrough  PCopyVariant=Disabled  TRVariant=Disabled  FdbkBlocksVariant=Forward  IdealPFdbkVariant=Disabled  SatFdbkVariant=Disabled  DerivativeFilterVariant=Disabled  NVariant=Disabled  NCopyVariant=Disabled_SignalSpec  FilterICVariant=Disabled  IntegratorICVariant=InternalICs  ExternalResetVariant=Disabled  TRSumVariant=Passthrough  SumFdbkVariant=Disabled  SumVariant=Sum_PI  TsampFilterVariant=InternalTs  TsampNgainVariant=Passthrough  TsampIntegralVariant=Disabled_SignalSpec  ExternalSaturationOutDataTypeStr=Inherit: Same as second input
  Discrete PID Controller3 : slpidlib/PID Controller  Controller=PI  Form=Parallel  TimeDomain=Discrete-time  UseExternalTs=off  SampleTime=Ts  IntegratorMethod=Forward Euler  FilterMethod=Forward Euler  ControllerParametersSource=internal  P=Kp_cc2  I=Ki_cc2  UseKiTs=off  D=0  N=100  UseFilter=on  TunerSelectOption=Transfer Function Based (PID Tuner App)  InitialConditionSource=internal  InitialConditionForIntegrator=0  InitialConditionForFilter=0  DifferentiatorICPrevScaledInput=0  ExternalReset=none  TrackingMode=off  Kt=1  LimitOutput=off  SatLimitsSource=internal  UpperSaturationLimit=inf  LowerSaturationLimit=-inf  LinearizeAsGain=off  AntiWindupMode=none  Kb=1  LimitIntegrator=off  UpperIntegratorSaturationLimit=inf  LowerIntegratorSaturationLimit=-inf  POutMin=[]  POutMax=[]  IOutMin=[]  IOutMax=[]  DOutMin=[]  DOutMax=[]  NOutMin=[]  NOutMax=[]  SumOutMin=[]  SumOutMax=[]  SaturationOutMin=[]  SaturationOutMax=[]  PParamMin=[]  PParamMax=[]  IParamMin=[]  IParamMax=[]  DParamMin=[]  DParamMax=[]  NParamMin=[]  NParamMax=[]  KbParamMin=[]  KbParamMax=[]  KtParamMin=[]  KtParamMax=[]  KbOutMin=[]  KbOutMax=[]  KtOutMin=[]  KtOutMax=[]  IntegratorOutMin=[]  IntegratorOutMax=[]  FilterOutMin=[]  FilterOutMax=[]  SumI1OutMin=[]  SumI1OutMax=[]  SumI2OutMin=[]  SumI2OutMax=[]  SumI3OutMin=[]  SumI3OutMax=[]  SumI4OutMin=[]  SumI4OutMax=[]  SumDOutMin=[]  SumDOutMax=[]  DifferentiatorOutMin=[]  DifferentiatorOutMax=[]  FilterDiffOutCoefMin=[]  FilterDiffOutCoefMax=[]  ReciprocalOutMin=[]  ReciprocalOutMax=[]  SumDenOutMin=[]  SumDenOutMax=[]  SumNumOutMin=[]  SumNumOutMax=[]  DivideOutMin=[]  DivideOutMax=[]  UdiffTsProdOutMin=[]  UdiffTsProdOutMax=[]  NTsProdOutMin=[]  NTsProdOutMax=[]  UintegralTsProdOutMin=[]  UintegralTsProdOutMax=[]  UngainTsProdOutMin=[]  UngainTsProdOutMax=[]  ClampingZeroOutDataTypeStr=Inherit: Inherit via back propagation  ClampingZeroOutMin=[]  ClampingZeroOutMax=[]  FilterDenConstantOutDataTypeStr=Inherit: Inherit via back propagation  FilterDenConstantOutMin=[]  FilterDenConstantOutMax=[]  PCopyOutDataTypeStr=Inherit: Inherit via back propagation  PCopyOutMin=[]  PCopyOutMax=[]  NCopyOutDataTypeStr=Inherit: Inherit via back propagation  NCopyOutMin=[]  NCopyOutMax=[]  IntegratorContinuousStateAttributes=''  IntegratorStateMustResolveToSignalObject=off  IntegratorRTWStateStorageClass=Auto  FilterContinuousStateAttributes=''  FilterStateMustResolveToSignalObject=off  FilterRTWStateStorageClass=Auto  ParallelPVariant=InternalParameters  IdealPVariant=Disabled  IVariant=InternalParameters  DVariant=Disabled  IntegratorVariant=Discrete  SatVariant=Disabled  AWVariant=Passthrough  PCopyVariant=Disabled  TRVariant=Disabled  FdbkBlocksVariant=Forward  IdealPFdbkVariant=Disabled  SatFdbkVariant=Disabled  DerivativeFilterVariant=Disabled  NVariant=Disabled  NCopyVariant=Disabled_SignalSpec  FilterICVariant=Disabled  IntegratorICVariant=InternalICs  ExternalResetVariant=Disabled  TRSumVariant=Passthrough  SumFdbkVariant=Disabled  SumVariant=Sum_PI  TsampFilterVariant=InternalTs  TsampNgainVariant=Passthrough  TsampIntegralVariant=Disabled_SignalSpec  ExternalSaturationOutDataTypeStr=Inherit: Same as second input
  Gain : Gain  Gain=Cf2
  Gain1 : Gain  Gain=Cf2
  Gain2 : Gain  Gain=Lf2
  Gain3 : Gain  Gain=Kffi2
  Gain4 : Gain  Gain=Lf2
  Gain5 : Gain  Gain=Kffi2
  Gain6 : Gain  Gain=Kffv2
  Gain7 : Gain  Gain=Kffv2
  Product{5..8} (4 alike) : Product
  Saturation2 : Saturate  UpperLimit=1.2*0.142*10e6  LowerLimit=-1.2*0.142*10e6  LinearizeAsGain=off  ZeroCross=off
  Saturation3 : Saturate  UpperLimit=1.2*0.106*10e6  LowerLimit=-1.2*0.106*10e6  LinearizeAsGain=off  ZeroCross=off
  Sum : Sum  Inputs=|+-
  Sum10 : Sum  Inputs=-+|
  Sum11 : Sum  Inputs=+++
  Sum12 : Sum  Inputs=|+-
  Sum13 : Sum  Inputs=-+|
  Sum14 : Sum  Inputs=++-
  Sum15 : Sum  Inputs=+++
  Sum7 : Sum  Inputs=++-
  Vd inverter : Outport
  Vq inverter : Outport  Port=2
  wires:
  [Vq1] -> Sum10/1, Product6/2
  Itd/1 -> Sum12/2, Product7/1
  Sum/1 -> Discrete PID Controller/1
  [w1] -> Product8/1
  Iq/1 -> Gain5/1
  Vd_ref/1 -> Sum/1
  [Vq1] -> Gain7/1
  Gain2/1 -> Sum15/1
  [Vd1] -> Gain6/1
  [Vd1] -> Sum/2, Product5/1
  Product5/1 -> Gain/1
  [w1] -> Product5/2
  Sum10/1 -> Discrete PID Controller1/1
  Gain3/1 -> Sum7/1
  Itq/1 -> Sum13/1, Product8/2
  Sum15/1 -> Vq inverter/1  "Vq inverter"
  [w1] -> Product6/1
  Product6/1 -> Gain1/1
  Gain/1 -> Sum11/1
  [w1] -> Product7/2
  Sum12/1 -> Discrete PID Controller2/1
  Vq_ref/1 -> Sum10/2
  Discrete PID Controller/1 -> Sum7/2
  Gain5/1 -> Sum11/3
  Gain4/1 -> Sum14/3
  Sum13/1 -> Discrete PID Controller3/1
  Gain1/1 -> Sum7/3
  Sum14/1 -> Vd inverter/1  "Vd inverter"
  Id/1 -> Gain3/1
  Product7/1 -> Gain2/1
  Product8/1 -> Gain4/1
  Discrete PID Controller2/1 -> Sum14/2
  Discrete PID Controller1/1 -> Sum11/2
  Gain6/1 -> Sum14/1
  Discrete PID Controller3/1 -> Sum15/2
  Gain7/1 -> Sum15/3
  w/1 -> [w1]
  Vd/1 -> [Vd1]
  Vq/1 -> [Vq1]
  Sum7/1 -> Saturation2/1  "Itd-ref"
  Saturation2/1 -> Sum12/1
  Sum11/1 -> Saturation3/1  "itq-ref"
  Saturation3/1 -> Sum13/2

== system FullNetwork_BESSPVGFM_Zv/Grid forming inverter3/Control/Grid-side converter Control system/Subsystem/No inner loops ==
  Vd_ref : Inport
  Vq_ref : Inport  Port=2
  Vd inverter : Outport
  Vq inverter : Outport  Port=2
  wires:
  Vd_ref/1 -> Vd inverter/1
  Vq_ref/1 -> Vq inverter/1

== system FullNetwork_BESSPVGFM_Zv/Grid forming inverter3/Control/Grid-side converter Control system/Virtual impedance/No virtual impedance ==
  Vd_ref : Inport
  Vq_ref : Inport  Port=2
  Vd_ref* : Outport
  Vq_ref* : Outport  Port=2
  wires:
  Vd_ref/1 -> Vd_ref*/1
  Vq_ref/1 -> Vq_ref*/1

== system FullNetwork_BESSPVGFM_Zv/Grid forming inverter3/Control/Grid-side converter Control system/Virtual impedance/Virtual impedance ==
  Vd_ref : Inport
  Id : Inport  Port=2
  Iq : Inport  Port=3
  Vq_ref : Inport  Port=4
  Rvir1 : Gain  Gain=Xv2
  Rvir2 : Gain  Gain=10*Xv2
  Rvir3 : Gain  Gain=Xv2
  Rvir4 : Gain  Gain=10*Xv2
  Sum1 : Sum  Inputs=-+
  Sum2 : Sum  Inputs=--
  Sum3 : Sum  Inputs=|++++
  Sum4 : Sum  Inputs=+++|
  Sum5 : Sum  Inputs=|+-
  Sum6 : Sum  Inputs=|-+
  Sum7 : Sum  Inputs=-+
  Sum8 : Sum  Inputs=--
  T_power10 : powerlib_extras/Discrete  Control Blocks/Discrete 1st-Order Filter  FilterType=Lowpass  Tc=0.05  Ts=Ts  Initialize=on  Vac_Init=[0 0 0]  Vdc_Init=1  PlotResponse=off  param1=[1 200 0.1 ]
  T_power4 : powerlib_extras/Discrete  Control Blocks/Discrete 1st-Order Filter  FilterType=Lowpass  Tc=0.05  Ts=Ts  Initialize=on  Vac_Init=[0 0 0]  Vdc_Init=1  PlotResponse=off  param1=[1 200 0.1 ]
  Transfer Fcn (with initial outputs){1..4} (4 alike) : simulink_extras/Additional Linear/Transfer Fcn (with initial outputs)  N=[0.5*0.2 0 ]  D=[0.2 1]  Y0=0  U0=0
  Xvir1 : Gain  Gain=Rv2
  Xvir2 : Gain  Gain=10*Rv2
  Xvir3 : Gain  Gain=Rv2
  Xvir4 : Gain  Gain=10*Rv2
  Vd_ref* : Outport
  Vq_ref* : Outport  Port=2
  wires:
  Sum1/1 -> Sum3/4, T_power10/1
  Vq_ref/1 -> Sum4/2
  Id/1 -> [Id2]
  Iq/1 -> [Iq2]
  [Id2] -> Xvir1/1
  Xvir1/1 -> Sum1/1
  [Iq2] -> Rvir3/1
  Rvir3/1 -> Sum1/2
  Rvir1/1 -> Sum2/1
  [Id2] -> Rvir1/1
  [Iq2] -> Xvir3/1
  Xvir3/1 -> Sum2/2
  Sum5/1 -> Vd_ref*/1
  Sum3/1 -> Sum5/1
  Sum2/1 -> T_power4/1, Sum4/1
  Sum4/1 -> Sum6/2
  T_power4/1 -> Sum6/1
  Sum6/1 -> Vq_ref*/1
  T_power10/1 -> Sum5/2
  Vd_ref/1 -> Sum3/2
  Rvir2/1 -> Sum7/2
  Xvir2/1 -> Sum7/1
  Xvir4/1 -> Sum8/2
  Rvir4/1 -> Sum8/1
  Transfer Fcn (with initial outputs)2/1 -> Xvir2/1
  [Id2] -> Transfer Fcn (with initial outputs)2/1
  [Iq2] -> Transfer Fcn (with initial outputs)1/1
  Transfer Fcn (with initial outputs)1/1 -> Rvir2/1
  [Id2] -> Transfer Fcn (with initial outputs)3/1
  Transfer Fcn (with initial outputs)3/1 -> Rvir4/1
  [Iq2] -> Transfer Fcn (with initial outputs)4/1
  Transfer Fcn (with initial outputs)4/1 -> Xvir4/1
  Sum8/1 -> Sum4/3
  Sum7/1 -> Sum3/1
